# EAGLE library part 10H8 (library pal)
PAL

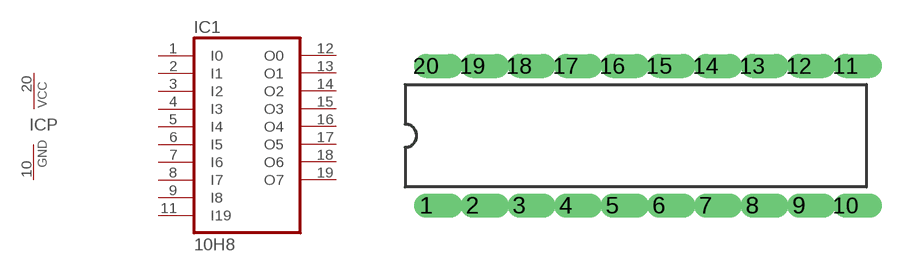
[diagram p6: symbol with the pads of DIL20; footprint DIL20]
Designator prefix IC; gates 1=10H8 P=PWRN

## 10H8  [DIL20]
1  1:I0  in
2  1:I1  in
3  1:I2  in
4  1:I3  in
5  1:I4  in
6  1:I5  in
7  1:I6  in
8  1:I7  in
9  1:I8  in
10  P:GND  pwr
11  1:I19  in
12  1:O0  out
13  1:O1  out
14  1:O2  out
15  1:O3  out
16  1:O4  out
17  1:O5  out
18  1:O6  out
19  1:O7  out
20  P:VCC  pwr

## Footprint DIL20 (pad centres in mm)
Dual In Line
drill 0.813 offset: 1 -11.43,-3.81; 2 -8.89,-3.81; 3 -6.35,-3.81; 4 -3.81,-3.81; 5 -1.27,-3.81; 6 1.27,-3.81; 7 3.81,-3.81; 8 6.35,-3.81; 9 8.89,-3.81; 10 11.43,-3.81; 11 11.43,3.81; 12 8.89,3.81; 13 6.35,3.81; 14 3.81,3.81; 15 1.27,3.81; 16 -1.27,3.81; 17 -3.81,3.81; 18 -6.35,3.81; 19 -8.89,3.81; 20 -11.43,3.81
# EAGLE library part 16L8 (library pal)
PAL

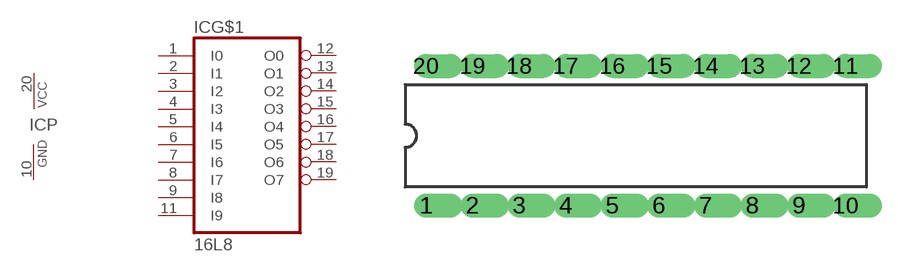
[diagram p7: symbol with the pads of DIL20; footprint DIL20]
Designator prefix IC; gates G$1=16L8 P=PWRN

## 16L8  [DIL20]
1  G$1:I0  in
2  G$1:I1  in
3  G$1:I2  in
4  G$1:I3  in
5  G$1:I4  in
6  G$1:I5  in
7  G$1:I6  in
8  G$1:I7  in
9  G$1:I8  in
10  P:GND  pwr
11  G$1:I9  in
12  G$1:O0  out
13  G$1:O1
14  G$1:O2
15  G$1:O3
16  G$1:O4
17  G$1:O5
18  G$1:O6
19  G$1:O7  out
20  P:VCC  pwr

## Footprint DIL20 (pad centres in mm)
Dual In Line
drill 0.813 offset: 1 -11.43,-3.81; 2 -8.89,-3.81; 3 -6.35,-3.81; 4 -3.81,-3.81; 5 -1.27,-3.81; 6 1.27,-3.81; 7 3.81,-3.81; 8 6.35,-3.81; 9 8.89,-3.81; 10 11.43,-3.81; 11 11.43,3.81; 12 8.89,3.81; 13 6.35,3.81; 14 3.81,3.81; 15 1.27,3.81; 16 -1.27,3.81; 17 -3.81,3.81; 18 -6.35,3.81; 19 -8.89,3.81; 20 -11.43,3.81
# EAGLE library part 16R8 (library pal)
PAL

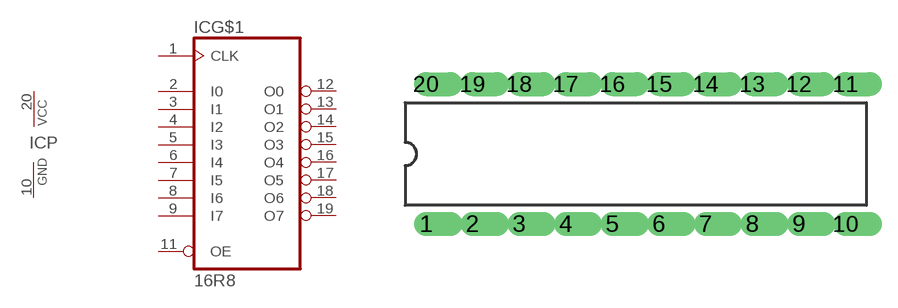
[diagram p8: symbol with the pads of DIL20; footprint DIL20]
Designator prefix IC; gates G$1=16R8 P=PWRN

## 16R8  [DIL20]
1  G$1:CLK  in
2  G$1:I0  in
3  G$1:I1  in
4  G$1:I2  in
5  G$1:I3  in
6  G$1:I4  in
7  G$1:I5  in
8  G$1:I6  in
9  G$1:I7  in
10  P:GND  pwr
11  G$1:OE  in
12  G$1:O0  out
13  G$1:O1  out
14  G$1:O2  out
15  G$1:O3  out
16  G$1:O4  out
17  G$1:O5  out
18  G$1:O6  out
19  G$1:O7  out
20  P:VCC  pwr

## Footprint DIL20 (pad centres in mm)
Dual In Line
drill 0.813 offset: 1 -11.43,-3.81; 2 -8.89,-3.81; 3 -6.35,-3.81; 4 -3.81,-3.81; 5 -1.27,-3.81; 6 1.27,-3.81; 7 3.81,-3.81; 8 6.35,-3.81; 9 8.89,-3.81; 10 11.43,-3.81; 11 11.43,3.81; 12 8.89,3.81; 13 6.35,3.81; 14 3.81,3.81; 15 1.27,3.81; 16 -1.27,3.81; 17 -3.81,3.81; 18 -6.35,3.81; 19 -8.89,3.81; 20 -11.43,3.81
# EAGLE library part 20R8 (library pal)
PAL

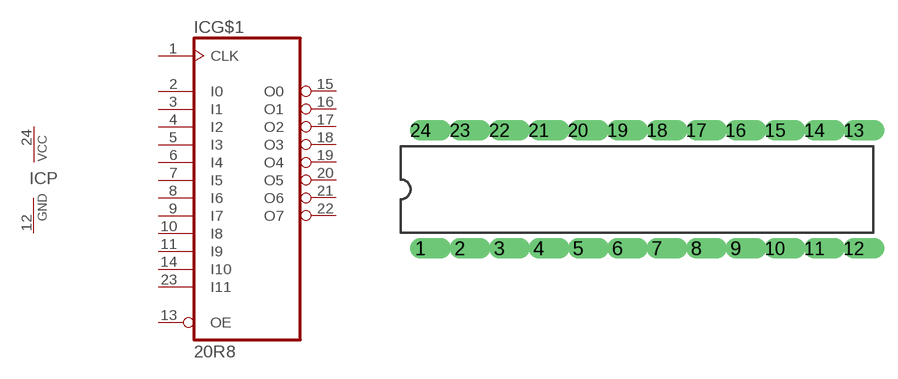
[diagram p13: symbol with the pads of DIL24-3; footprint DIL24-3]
Designator prefix IC; gates G$1=20R8 P=PWRN

## 20R8  [DIL24-3]
1  G$1:CLK  in
2  G$1:I0  in
3  G$1:I1  in
4  G$1:I2  in
5  G$1:I3  in
6  G$1:I4  in
7  G$1:I5  in
8  G$1:I6  in
9  G$1:I7  in
10  G$1:I8  in
11  G$1:I9  in
12  P:GND  pwr
13  G$1:OE  in
14  G$1:I10  in
15  G$1:O0  out
16  G$1:O1  out
17  G$1:O2  out
18  G$1:O3  out
19  G$1:O4  out
20  G$1:O5  out
21  G$1:O6  out
22  G$1:O7  out
23  G$1:I11  in
24  P:VCC  pwr

## Footprint DIL24-3 (pad centres in mm)
Dual In Line
drill 0.813 offset: 1 -13.97,-3.81; 2 -11.43,-3.81; 3 -8.89,-3.81; 4 -6.35,-3.81; 5 -3.81,-3.81; 6 -1.27,-3.81; 7 1.27,-3.81; 8 3.81,-3.81; 9 6.35,-3.81; 10 8.89,-3.81; 11 11.43,-3.81; 12 13.97,-3.81; 13 13.97,3.81; 14 11.43,3.81; 15 8.89,3.81; 16 6.35,3.81; 17 3.81,3.81; 18 1.27,3.81; 19 -1.27,3.81; 20 -3.81,3.81; 21 -6.35,3.81; 22 -8.89,3.81; 23 -11.43,3.81; 24 -13.97,3.81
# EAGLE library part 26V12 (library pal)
PAL

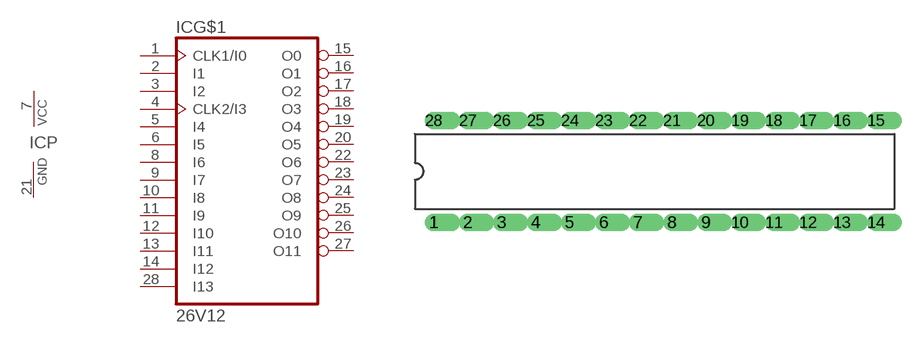
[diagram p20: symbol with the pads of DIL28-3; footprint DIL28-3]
Designator prefix IC; gates G$1=26V12 P=PWRN

## 26V12  [DIL28-3]
1  G$1:CLK1/I0  in
2  G$1:I1  in
3  G$1:I2  in
4  G$1:CLK2/I3  in
5  G$1:I4  in
6  G$1:I5  in
7  P:VCC  pwr
8  G$1:I6  in
9  G$1:I7  in
10  G$1:I8  in
11  G$1:I9  in
12  G$1:I10  in
13  G$1:I11  in
14  G$1:I12  in
15  G$1:O0
16  G$1:O1
17  G$1:O2
18  G$1:O3
19  G$1:O4
20  G$1:O5
21  P:GND  pwr
22  G$1:O6
23  G$1:O7
24  G$1:O8
25  G$1:O9
26  G$1:O10
27  G$1:O11
28  G$1:I13  in

## Footprint DIL28-3 (pad centres in mm)
Dual In Line
drill 0.813 offset: 1 -16.51,-3.81; 2 -13.97,-3.81; 3 -11.43,-3.81; 4 -8.89,-3.81; 5 -6.35,-3.81; 6 -3.81,-3.81; 7 -1.27,-3.81; 8 1.27,-3.81; 9 3.81,-3.81; 10 6.35,-3.81; 11 8.89,-3.81; 12 11.43,-3.81; 13 13.97,-3.81; 14 16.51,-3.81; 15 16.51,3.81; 16 13.97,3.81; 17 11.43,3.81; 18 8.89,3.81; 19 6.35,3.81; 20 3.81,3.81; 21 1.27,3.81; 22 -1.27,3.81; 23 -3.81,3.81; 24 -6.35,3.81; 25 -8.89,3.81; 26 -11.43,3.81; 27 -13.97,3.81; 28 -16.51,3.81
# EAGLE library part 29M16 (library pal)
PAL

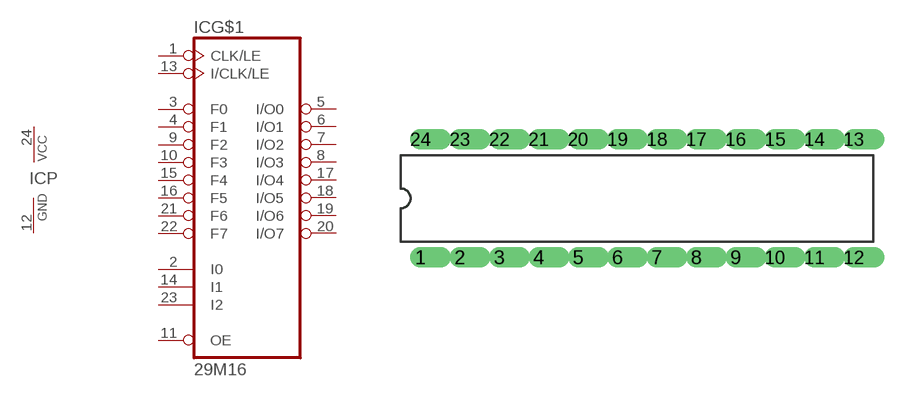
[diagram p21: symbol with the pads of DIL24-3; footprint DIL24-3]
Designator prefix IC; gates G$1=29M16 P=PWRN

## 29M16  [DIL24-3]
1  G$1:CLK/LE  in
2  G$1:I0  in
3  G$1:F0
4  G$1:F1
5  G$1:I/O0
6  G$1:I/O1
7  G$1:I/O2
8  G$1:I/O3
9  G$1:F2
10  G$1:F3
11  G$1:OE  in
12  P:GND  pwr
13  G$1:I/CLK/LE  in
14  G$1:I1  in
15  G$1:F4
16  G$1:F5
17  G$1:I/O4
18  G$1:I/O5
19  G$1:I/O6
20  G$1:I/O7
21  G$1:F6
22  G$1:F7
23  G$1:I2  in
24  P:VCC  pwr

## Footprint DIL24-3 (pad centres in mm)
Dual In Line
drill 0.813 offset: 1 -13.97,-3.81; 2 -11.43,-3.81; 3 -8.89,-3.81; 4 -6.35,-3.81; 5 -3.81,-3.81; 6 -1.27,-3.81; 7 1.27,-3.81; 8 3.81,-3.81; 9 6.35,-3.81; 10 8.89,-3.81; 11 11.43,-3.81; 12 13.97,-3.81; 13 13.97,3.81; 14 11.43,3.81; 15 8.89,3.81; 16 6.35,3.81; 17 3.81,3.81; 18 1.27,3.81; 19 -1.27,3.81; 20 -3.81,3.81; 21 -6.35,3.81; 22 -8.89,3.81; 23 -11.43,3.81; 24 -13.97,3.81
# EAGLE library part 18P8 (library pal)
PAL

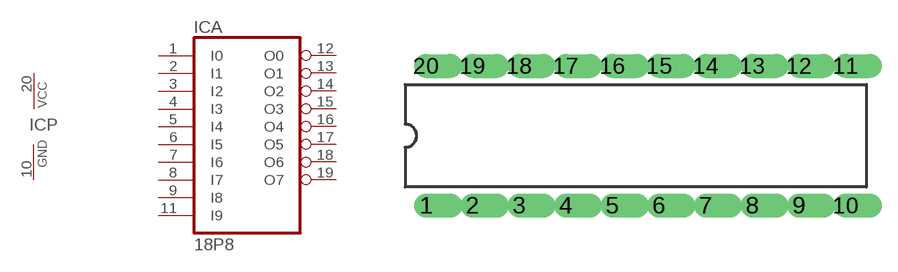
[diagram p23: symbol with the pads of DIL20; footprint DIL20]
Designator prefix IC; gates A=18P8 P=PWRN

## 18P8  [DIL20]
1  A:I0  in
2  A:I1  in
3  A:I2  in
4  A:I3  in
5  A:I4  in
6  A:I5  in
7  A:I6  in
8  A:I7  in
9  A:I8  in
10  P:GND  pwr
11  A:I9  in
12  A:O0
13  A:O1
14  A:O2
15  A:O3
16  A:O4
17  A:O5
18  A:O6
19  A:O7
20  P:VCC  pwr

## Footprint DIL20 (pad centres in mm)
Dual In Line
drill 0.813 offset: 1 -11.43,-3.81; 2 -8.89,-3.81; 3 -6.35,-3.81; 4 -3.81,-3.81; 5 -1.27,-3.81; 6 1.27,-3.81; 7 3.81,-3.81; 8 6.35,-3.81; 9 8.89,-3.81; 10 11.43,-3.81; 11 11.43,3.81; 12 8.89,3.81; 13 6.35,3.81; 14 3.81,3.81; 15 1.27,3.81; 16 -1.27,3.81; 17 -3.81,3.81; 18 -6.35,3.81; 19 -8.89,3.81; 20 -11.43,3.81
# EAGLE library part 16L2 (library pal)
PAL

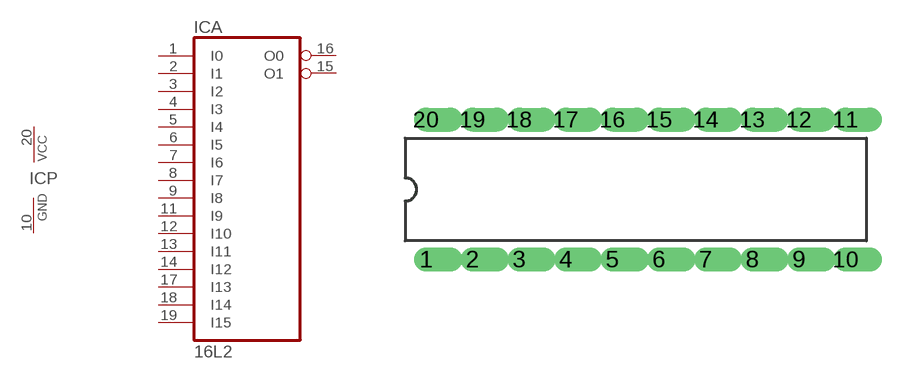
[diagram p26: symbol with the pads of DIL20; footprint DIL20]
Designator prefix IC; gates A=16L2 P=PWRN

## 16L2  [DIL20]
1  A:I0  in
2  A:I1  in
3  A:I2  in
4  A:I3  in
5  A:I4  in
6  A:I5  in
7  A:I6  in
8  A:I7  in
9  A:I8  in
10  P:GND  pwr
11  A:I9  in
12  A:I10  in
13  A:I11  in
14  A:I12  in
15  A:O1  out
16  A:O0  out
17  A:I13  in
18  A:I14  in
19  A:I15  in
20  P:VCC  pwr

## Footprint DIL20 (pad centres in mm)
Dual In Line
drill 0.813 offset: 1 -11.43,-3.81; 2 -8.89,-3.81; 3 -6.35,-3.81; 4 -3.81,-3.81; 5 -1.27,-3.81; 6 1.27,-3.81; 7 3.81,-3.81; 8 6.35,-3.81; 9 8.89,-3.81; 10 11.43,-3.81; 11 11.43,3.81; 12 8.89,3.81; 13 6.35,3.81; 14 3.81,3.81; 15 1.27,3.81; 16 -1.27,3.81; 17 -3.81,3.81; 18 -6.35,3.81; 19 -8.89,3.81; 20 -11.43,3.81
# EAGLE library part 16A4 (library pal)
PAL

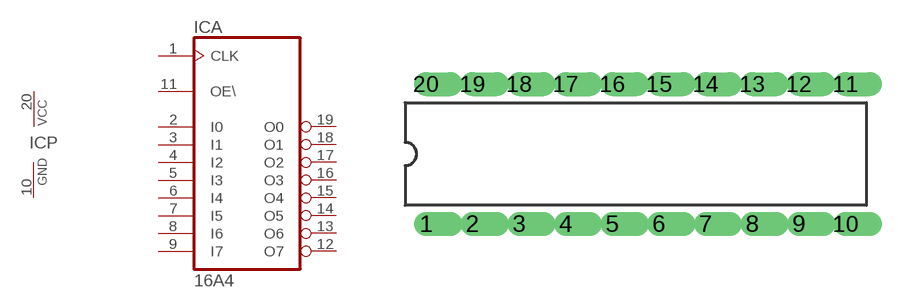
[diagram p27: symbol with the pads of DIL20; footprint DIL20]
Designator prefix IC; gates A=16A4 P=PWRN

## 16A4  [DIL20]
1  A:CLK  in
2  A:I0  in
3  A:I1  in
4  A:I2  in
5  A:I3  in
6  A:I4  in
7  A:I5  in
8  A:I6  in
9  A:I7  in
10  P:GND  pwr
11  A:OE\  in
12  A:O7
13  A:O6
14  A:O5  hiz
15  A:O4  hiz
16  A:O3  hiz
17  A:O2  hiz
18  A:O1
19  A:O0
20  P:VCC  pwr

## Footprint DIL20 (pad centres in mm)
Dual In Line
drill 0.813 offset: 1 -11.43,-3.81; 2 -8.89,-3.81; 3 -6.35,-3.81; 4 -3.81,-3.81; 5 -1.27,-3.81; 6 1.27,-3.81; 7 3.81,-3.81; 8 6.35,-3.81; 9 8.89,-3.81; 10 11.43,-3.81; 11 11.43,3.81; 12 8.89,3.81; 13 6.35,3.81; 14 3.81,3.81; 15 1.27,3.81; 16 -1.27,3.81; 17 -3.81,3.81; 18 -6.35,3.81; 19 -8.89,3.81; 20 -11.43,3.81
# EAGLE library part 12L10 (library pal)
PAL

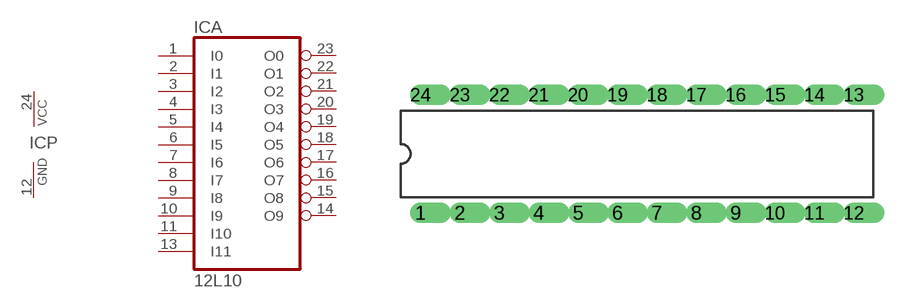
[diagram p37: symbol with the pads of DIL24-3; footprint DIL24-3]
Designator prefix IC; gates A=12L10 P=PWRN

## 12L10  [DIL24-3]
1  A:I0  in
2  A:I1  in
3  A:I2  in
4  A:I3  in
5  A:I4  in
6  A:I5  in
7  A:I6  in
8  A:I7  in
9  A:I8  in
10  A:I9  in
11  A:I10  in
12  P:GND  pwr
13  A:I11  in
14  A:O9  out
15  A:O8  out
16  A:O7  out
17  A:O6  out
18  A:O5  out
19  A:O4  out
20  A:O3  out
21  A:O2  out
22  A:O1  out
23  A:O0  out
24  P:VCC  pwr

## Footprint DIL24-3 (pad centres in mm)
Dual In Line
drill 0.813 offset: 1 -13.97,-3.81; 2 -11.43,-3.81; 3 -8.89,-3.81; 4 -6.35,-3.81; 5 -3.81,-3.81; 6 -1.27,-3.81; 7 1.27,-3.81; 8 3.81,-3.81; 9 6.35,-3.81; 10 8.89,-3.81; 11 11.43,-3.81; 12 13.97,-3.81; 13 13.97,3.81; 14 11.43,3.81; 15 8.89,3.81; 16 6.35,3.81; 17 3.81,3.81; 18 1.27,3.81; 19 -1.27,3.81; 20 -3.81,3.81; 21 -6.35,3.81; 22 -8.89,3.81; 23 -11.43,3.81; 24 -13.97,3.81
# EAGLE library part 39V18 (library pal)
PAL

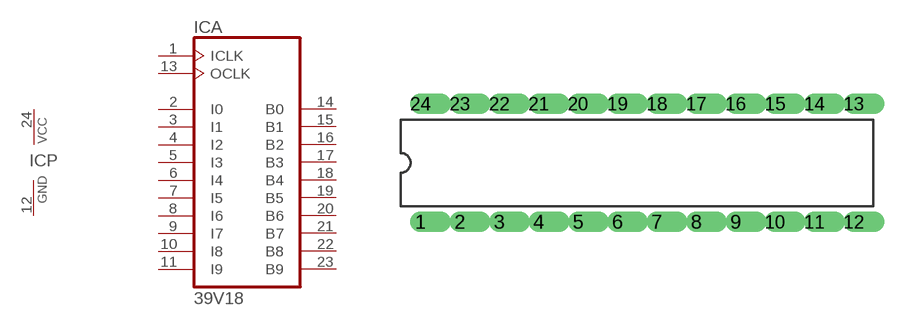
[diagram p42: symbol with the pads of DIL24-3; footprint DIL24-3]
Designator prefix IC; gates A=39V18 P=PWRN

## 39V18  [DIL24-3]
1  A:ICLK  in
2  A:I0  in
3  A:I1  in
4  A:I2  in
5  A:I3  in
6  A:I4  in
7  A:I5  in
8  A:I6  in
9  A:I7  in
10  A:I8  in
11  A:I9  in
12  P:GND  pwr
13  A:OCLK  in
14  A:B0
15  A:B1
16  A:B2
17  A:B3
18  A:B4
19  A:B5
20  A:B6
21  A:B7
22  A:B8
23  A:B9
24  P:VCC  pwr

## Footprint DIL24-3 (pad centres in mm)
Dual In Line
drill 0.813 offset: 1 -13.97,-3.81; 2 -11.43,-3.81; 3 -8.89,-3.81; 4 -6.35,-3.81; 5 -3.81,-3.81; 6 -1.27,-3.81; 7 1.27,-3.81; 8 3.81,-3.81; 9 6.35,-3.81; 10 8.89,-3.81; 11 11.43,-3.81; 12 13.97,-3.81; 13 13.97,3.81; 14 11.43,3.81; 15 8.89,3.81; 16 6.35,3.81; 17 3.81,3.81; 18 1.27,3.81; 19 -1.27,3.81; 20 -3.81,3.81; 21 -6.35,3.81; 22 -8.89,3.81; 23 -11.43,3.81; 24 -13.97,3.81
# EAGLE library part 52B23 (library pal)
PAL

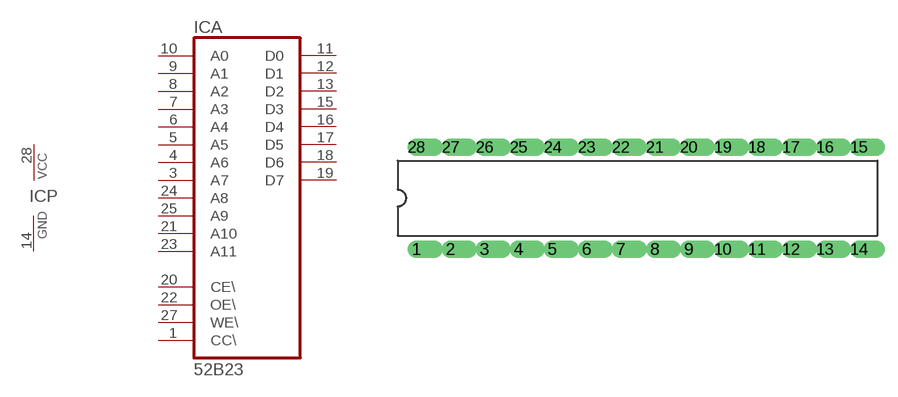
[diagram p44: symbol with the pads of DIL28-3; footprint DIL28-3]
Designator prefix IC; gates A=52B23 P=PWRN

## 52B23  [DIL28-3]
1  A:CC\  in
3  A:A7  in
4  A:A6  in
5  A:A5  in
6  A:A4  in
7  A:A3  in
8  A:A2  in
9  A:A1  in
10  A:A0  in
11  A:D0  hiz
12  A:D1  hiz
13  A:D2  hiz
14  P:GND  pwr
15  A:D3  hiz
16  A:D4  hiz
17  A:D5  hiz
18  A:D6  hiz
19  A:D7  hiz
20  A:CE\  in
21  A:A10  in
22  A:OE\  in
23  A:A11  in
24  A:A8  in
25  A:A9  in
27  A:WE\  in
28  P:VCC  pwr

## Footprint DIL28-3 (pad centres in mm)
Dual In Line
drill 0.813 offset: 1 -16.51,-3.81; 2 -13.97,-3.81; 3 -11.43,-3.81; 4 -8.89,-3.81; 5 -6.35,-3.81; 6 -3.81,-3.81; 7 -1.27,-3.81; 8 1.27,-3.81; 9 3.81,-3.81; 10 6.35,-3.81; 11 8.89,-3.81; 12 11.43,-3.81; 13 13.97,-3.81; 14 16.51,-3.81; 15 16.51,3.81; 16 13.97,3.81; 17 11.43,3.81; 18 8.89,3.81; 19 6.35,3.81; 20 3.81,3.81; 21 1.27,3.81; 22 -1.27,3.81; 23 -3.81,3.81; 24 -6.35,3.81; 25 -8.89,3.81; 26 -11.43,3.81; 27 -13.97,3.81; 28 -16.51,3.81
